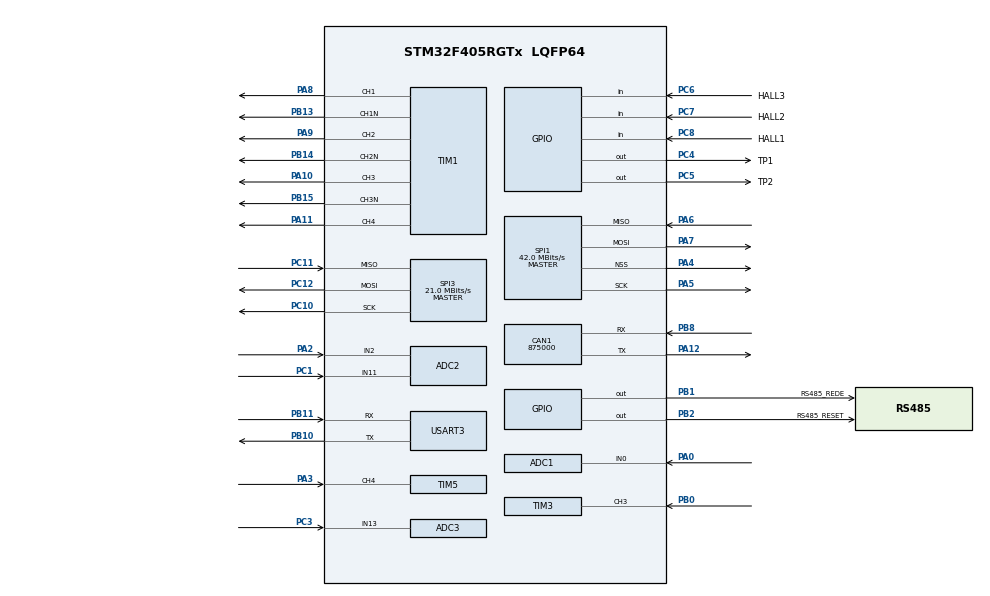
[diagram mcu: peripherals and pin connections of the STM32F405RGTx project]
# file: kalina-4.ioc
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ADC1.Channel-0\#ChannelRegularConversion=ADC_CHANNEL_0
ADC1.Channel-1\#ChannelInjectedConversion=ADC_CHANNEL_0
ADC1.Channel-2\#ChannelInjectedConversion=ADC_CHANNEL_TEMPSENSOR
ADC1.Channel-3\#ChannelInjectedConversion=ADC_CHANNEL_VREFINT
ADC1.ClockPrescaler=ADC_CLOCK_SYNC_PCLK_DIV6
ADC1.InjNumberOfConversion=3
ADC1.InjectedOffset-1\#ChannelInjectedConversion=0
ADC1.InjectedOffset-2\#ChannelInjectedConversion=0
ADC1.InjectedOffset-3\#ChannelInjectedConversion=0
ADC1.InjectedRank-1\#ChannelInjectedConversion=1
ADC1.InjectedRank-2\#ChannelInjectedConversion=2
ADC1.InjectedRank-3\#ChannelInjectedConversion=3
ADC1.NbrOfConversion=1
ADC1.NbrOfConversionFlag=1
ADC1.Rank-0\#ChannelRegularConversion=1
ADC1.SamplingTime-0\#ChannelRegularConversion=ADC_SAMPLETIME_3CYCLES
ADC1.SamplingTime-1\#ChannelInjectedConversion=ADC_SAMPLETIME_3CYCLES
ADC1.SamplingTime-2\#ChannelInjectedConversion=ADC_SAMPLETIME_3CYCLES
ADC1.SamplingTime-3\#ChannelInjectedConversion=ADC_SAMPLETIME_3CYCLES
ADC1.master=1
ADC2.Channel-0\#ChannelRegularConversion=ADC_CHANNEL_2
ADC2.Channel-1\#ChannelInjectedConversion=ADC_CHANNEL_2
ADC2.Channel-2\#ChannelInjectedConversion=ADC_CHANNEL_11
ADC2.ClockPrescaler=ADC_CLOCK_SYNC_PCLK_DIV6
ADC2.InjNumberOfConversion=2
ADC2.InjectedOffset-1\#ChannelInjectedConversion=0
ADC2.InjectedOffset-2\#ChannelInjectedConversion=0
ADC2.InjectedRank-1\#ChannelInjectedConversion=1
ADC2.InjectedRank-2\#ChannelInjectedConversion=2
ADC2.NbrOfConversionFlag=1
ADC2.Rank-0\#ChannelRegularConversion=1
ADC2.SamplingTime-0\#ChannelRegularConversion=ADC_SAMPLETIME_3CYCLES
ADC2.SamplingTime-1\#ChannelInjectedConversion=ADC_SAMPLETIME_3CYCLES
ADC2.SamplingTime-2\#ChannelInjectedConversion=ADC_SAMPLETIME_3CYCLES
ADC3.Channel-0\#ChannelRegularConversion=ADC_CHANNEL_13
ADC3.Channel-1\#ChannelInjectedConversion=ADC_CHANNEL_13
ADC3.ClockPrescaler=ADC_CLOCK_SYNC_PCLK_DIV6
ADC3.InjNumberOfConversion=1
ADC3.InjectedOffset-1\#ChannelInjectedConversion=0
ADC3.InjectedRank-1\#ChannelInjectedConversion=1
ADC3.NbrOfConversion=1
ADC3.NbrOfConversionFlag=1
ADC3.Rank-0\#ChannelRegularConversion=1
ADC3.SamplingTime-0\#ChannelRegularConversion=ADC_SAMPLETIME_3CYCLES
ADC3.SamplingTime-1\#ChannelInjectedConversion=ADC_SAMPLETIME_3CYCLES
ADC3.ScanConvMode=ENABLE
CAN1.BS1=CAN_BS1_1TQ
CAN1.BS2=CAN_BS2_1TQ
CAN1.CalculateBaudRate=875000
CAN1.CalculateTimeBit=1142
CAN1.CalculateTimeQuantum=380.95238095238096
Dma.Request0=USART3_RX
Dma.Request1=USART3_TX
Dma.USART3_RX.0.Direction=DMA_PERIPH_TO_MEMORY
Dma.USART3_RX.0.FIFOMode=DMA_FIFOMODE_DISABLE
Dma.USART3_RX.0.Instance=DMA1_Stream1
Dma.USART3_RX.0.MemDataAlignment=DMA_MDATAALIGN_BYTE
Dma.USART3_RX.0.MemInc=DMA_MINC_ENABLE
Dma.USART3_RX.0.Mode=DMA_NORMAL
Dma.USART3_RX.0.PeriphDataAlignment=DMA_PDATAALIGN_BYTE
Dma.USART3_RX.0.PeriphInc=DMA_PINC_DISABLE
Dma.USART3_RX.0.Priority=DMA_PRIORITY_LOW
Dma.USART3_TX.1.Direction=DMA_MEMORY_TO_PERIPH
Dma.USART3_TX.1.FIFOMode=DMA_FIFOMODE_DISABLE
Dma.USART3_TX.1.Instance=DMA1_Stream3
Dma.USART3_TX.1.MemDataAlignment=DMA_MDATAALIGN_BYTE
Dma.USART3_TX.1.MemInc=DMA_MINC_ENABLE
Dma.USART3_TX.1.Mode=DMA_NORMAL
Dma.USART3_TX.1.PeriphDataAlignment=DMA_PDATAALIGN_BYTE
Dma.USART3_TX.1.PeriphInc=DMA_PINC_DISABLE
Dma.USART3_TX.1.Priority=DMA_PRIORITY_LOW
Mcu.Family=STM32F4
Mcu.Name=STM32F405RGTx
Mcu.Package=LQFP64
NVIC.DMA1_Stream1_IRQn=true\:0\:0\:false\:false\:true\:false\:true\:true
NVIC.DMA1_Stream3_IRQn=true\:0\:0\:false\:false\:true\:false\:true\:true
NVIC.PriorityGroup=NVIC_PRIORITYGROUP_4
NVIC.TIM3_IRQn=true\:15\:0\:true\:false\:true\:true\:true\:true
NVIC.TIM5_IRQn=true\:15\:0\:true\:false\:true\:true\:true\:true
NVIC.USART3_IRQn=true\:15\:0\:true\:false\:true\:true\:true\:true
PA0-WKUP.Signal=ADCx_IN0
PA10.Signal=S_TIM1_CH3
PA11.Signal=S_TIM1_CH4
PA12.Mode=CAN_Activate
PA12.Signal=CAN1_TX
PA13.Mode=Serial_Wire
PA13.Signal=SYS_JTMS-SWDIO
PA14.Mode=Serial_Wire
PA14.Signal=SYS_JTCK-SWCLK
PA2.Signal=ADCx_IN2
PA3.Signal=S_TIM5_CH4
PA4.Mode=NSS_Signal_Hard_Output
PA4.Signal=SPI1_NSS
PA5.Mode=Full_Duplex_Master
PA5.Signal=SPI1_SCK
PA6.Mode=Full_Duplex_Master
PA6.Signal=SPI1_MISO
PA7.Mode=Full_Duplex_Master
PA7.Signal=SPI1_MOSI
PA8.Signal=S_TIM1_CH1
PA9.Signal=S_TIM1_CH2
PB0.Signal=S_TIM3_CH3
PB1.GPIO_Label=RS485_REDE
PB1.GPIO_Speed=GPIO_SPEED_FREQ_VERY_HIGH
PB1.Signal=GPIO_Output
PB10.Mode=Asynchronous
PB10.Signal=USART3_TX
PB11.Mode=Asynchronous
PB11.Signal=USART3_RX
PB13.Mode=PWM Generation1 CH1 CH1N
PB13.Signal=TIM1_CH1N
PB14.Mode=PWM Generation2 CH2 CH2N
PB14.Signal=TIM1_CH2N
PB15.Mode=PWM Generation3 CH3 CH3N
PB15.Signal=TIM1_CH3N
PB2.GPIO_Label=RS485_RESET
PB2.GPIO_Speed=GPIO_SPEED_FREQ_LOW
PB2.Signal=GPIO_Output
PB8.Mode=CAN_Activate
PB8.Signal=CAN1_RX
PC1.Signal=ADCx_IN11
PC10.Mode=Full_Duplex_Master
PC10.Signal=SPI3_SCK
PC11.Mode=Full_Duplex_Master
PC11.Signal=SPI3_MISO
PC12.Mode=Full_Duplex_Master
PC12.Signal=SPI3_MOSI
PC3.Signal=ADCx_IN13
PC4.GPIO_Label=TP1
PC4.Signal=GPIO_Output
PC5.GPIO_Label=TP2
PC5.Signal=GPIO_Output
PC6.GPIO_Label=HALL3
PC6.GPIO_PuPd=GPIO_NOPULL
PC6.Signal=GPIO_Input
PC7.GPIO_Label=HALL2
PC7.Signal=GPIO_Input
PC8.GPIO_Label=HALL1
PC8.Signal=GPIO_Input
PH0-OSC_IN.Mode=HSE-External-Oscillator
PH0-OSC_IN.Signal=RCC_OSC_IN
PH1-OSC_OUT.Mode=HSE-External-Oscillator
PH1-OSC_OUT.Signal=RCC_OSC_OUT
ProjectManager.HeapSize=0x1000
ProjectManager.StackSize=0x400
ProjectManager.TargetToolchain=MDK-ARM V5.32
RCC.48MHZClocksFreq_Value=84000000
RCC.AHBFreq_Value=168000000
RCC.APB1CLKDivider=RCC_HCLK_DIV4
RCC.APB1Freq_Value=42000000
RCC.APB1TimFreq_Value=84000000
RCC.APB2CLKDivider=RCC_HCLK_DIV2
RCC.APB2Freq_Value=84000000
RCC.APB2TimFreq_Value=168000000
RCC.CortexFreq_Value=168000000
RCC.HCLKFreq_Value=168000000
RCC.HSE_VALUE=12000000
RCC.HSI_VALUE=16000000
RCC.LSE_VALUE=32768
RCC.PLLM=6
RCC.PLLN=168
RCC.PLLSourceVirtual=RCC_PLLSOURCE_HSE
RCC.SYSCLKFreq_VALUE=168000000
RCC.SYSCLKSource=RCC_SYSCLKSOURCE_PLLCLK
RCC.VCOOutputFreq_Value=336000000
SH.ADCx_IN0.0=ADC1_IN0,IN0
SH.ADCx_IN11.0=ADC2_IN11,IN11
SH.ADCx_IN13.0=ADC3_IN13,IN13
SH.ADCx_IN2.0=ADC2_IN2,IN2
SH.S_TIM1_CH1.0=TIM1_CH1,PWM Generation1 CH1 CH1N
SH.S_TIM1_CH2.0=TIM1_CH2,PWM Generation2 CH2 CH2N
SH.S_TIM1_CH3.0=TIM1_CH3,PWM Generation3 CH3 CH3N
SH.S_TIM1_CH4.0=TIM1_CH4,Output Compare4 CH4
SH.S_TIM3_CH3.0=TIM3_CH3,Input_Capture3_from_TI3
SH.S_TIM5_CH4.0=TIM5_CH4,Input_Capture4_from_TI4
SPI1.BaudRatePrescaler=SPI_BAUDRATEPRESCALER_2
SPI1.CalculateBaudRate=42.0 MBits/s
SPI1.Direction=SPI_DIRECTION_2LINES
SPI1.Mode=SPI_MODE_MASTER
SPI1.VirtualNSS=VM_NSSHARD
SPI1.VirtualType=VM_MASTER
SPI3.BaudRatePrescaler=SPI_BAUDRATEPRESCALER_2
SPI3.CalculateBaudRate=21.0 MBits/s
SPI3.Direction=SPI_DIRECTION_2LINES
SPI3.Mode=SPI_MODE_MASTER
SPI3.VirtualType=VM_MASTER
TIM1.Channel-Output\ Compare4\ CH4=TIM_CHANNEL_4
TIM1.Channel-PWM\ Generation1\ CH1\ CH1N=TIM_CHANNEL_1
TIM1.Channel-PWM\ Generation2\ CH2\ CH2N=TIM_CHANNEL_2
TIM1.Channel-PWM\ Generation3\ CH3\ CH3N=TIM_CHANNEL_3
TIM1.CounterMode=TIM_COUNTERMODE_CENTERALIGNED2
TIM1.DeadTime=127
TIM3.Channel-Input_Capture3_from_TI3=TIM_CHANNEL_3
TIM3.ICPolarity_CH3=TIM_INPUTCHANNELPOLARITY_BOTHEDGE
TIM5.Channel-Input_Capture4_from_TI4=TIM_CHANNEL_4
TIM5.ICPolarity_CH4=TIM_INPUTCHANNELPOLARITY_BOTHEDGE
USART3.VirtualMode=VM_ASYNC
VP_ADC1_TempSens_Input.Mode=IN-TempSens
VP_ADC1_Vref_Input.Mode=IN-Vrefint
board=custom

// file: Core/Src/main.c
/* USER CODE BEGIN Header */
/**
  ******************************************************************************
  * @file           : main.c
  * @brief          : Main program body
  ******************************************************************************
  * @attention
  *
  * Copyright (c) 2023 STMicroelectronics.
  * All rights reserved.
  *
  * This software is licensed under terms that can be found in the LICENSE file
  * in the root directory of this software component.
  * If no LICENSE file comes with this software, it is provided AS-IS.
  *
  ******************************************************************************
  */
/* USER CODE END Header */
#include "main.h"
#include "adc.h"
#include "can.h"
#include "dma.h"
#include "spi.h"
#include "tim.h"
#include "usart.h"
#include "gpio.h"

/* USER CODE BEGIN Includes */
#include "burst/burst.h"
/* USER CODE END Includes */

void SystemClock_Config(void);

int main(void)
{

  /* MCU Configuration--------------------------------------------------------*/

  /* Reset of all peripherals, Initializes the Flash interface and the Systick. */
  HAL_Init();

  /* Configure the system clock */
  SystemClock_Config();

  /* Initialize all configured peripherals */
  MX_GPIO_Init();
  MX_DMA_Init();
  MX_ADC1_Init();
  MX_ADC2_Init();
  MX_ADC3_Init();
  MX_CAN1_Init();
  MX_SPI1_Init();
  MX_SPI3_Init();
  MX_TIM1_Init();
  MX_TIM3_Init();
  MX_TIM5_Init();
  MX_USART3_UART_Init();
  /* USER CODE BEGIN 2 */
	burst_begin();
	burst_start();
  /* USER CODE END 2 */

  /* Infinite loop */
  /* USER CODE BEGIN WHILE */
  while (1)
  {
		burst_frontend_loop();
    /* USER CODE END WHILE */

  }
}

void SystemClock_Config(void)
{
  RCC_OscInitTypeDef RCC_OscInitStruct = {0};
  RCC_ClkInitTypeDef RCC_ClkInitStruct = {0};

  /** Configure the main internal regulator output voltage
  */
  __HAL_RCC_PWR_CLK_ENABLE();
  __HAL_PWR_VOLTAGESCALING_CONFIG(PWR_REGULATOR_VOLTAGE_SCALE1);

  /** Initializes the RCC Oscillators according to the specified parameters
  * in the RCC_OscInitTypeDef structure.
  */
  RCC_OscInitStruct.OscillatorType = RCC_OSCILLATORTYPE_LSI|RCC_OSCILLATORTYPE_HSE;
  RCC_OscInitStruct.HSEState = RCC_HSE_ON;
  RCC_OscInitStruct.LSIState = RCC_LSI_ON;
  RCC_OscInitStruct.PLL.PLLState = RCC_PLL_ON;
  RCC_OscInitStruct.PLL.PLLSource = RCC_PLLSOURCE_HSE;
  RCC_OscInitStruct.PLL.PLLM = 6;
  RCC_OscInitStruct.PLL.PLLN = 72;
  RCC_OscInitStruct.PLL.PLLP = RCC_PLLP_DIV2;
  RCC_OscInitStruct.PLL.PLLQ = 4;
  if (HAL_RCC_OscConfig(&RCC_OscInitStruct) != HAL_OK)
  {
    Error_Handler();
  }

  /** Initializes the CPU, AHB and APB buses clocks
  */
  RCC_ClkInitStruct.ClockType = RCC_CLOCKTYPE_HCLK|RCC_CLOCKTYPE_SYSCLK
                              |RCC_CLOCKTYPE_PCLK1|RCC_CLOCKTYPE_PCLK2;
  RCC_ClkInitStruct.SYSCLKSource = RCC_SYSCLKSOURCE_PLLCLK;
  RCC_ClkInitStruct.AHBCLKDivider = RCC_SYSCLK_DIV1;
  RCC_ClkInitStruct.APB1CLKDivider = RCC_HCLK_DIV2;
  RCC_ClkInitStruct.APB2CLKDivider = RCC_HCLK_DIV2;

  if (HAL_RCC_ClockConfig(&RCC_ClkInitStruct, FLASH_LATENCY_2) != HAL_OK)
  {
    Error_Handler();
  }
}

void Error_Handler(void)
{
  /* USER CODE BEGIN Error_Handler_Debug */
  /* User can add his own implementation to report the HAL error return state */
		burst_crash();
  __disable_irq();
  while (1)
  {
  }
  /* USER CODE END Error_Handler_Debug */
}
